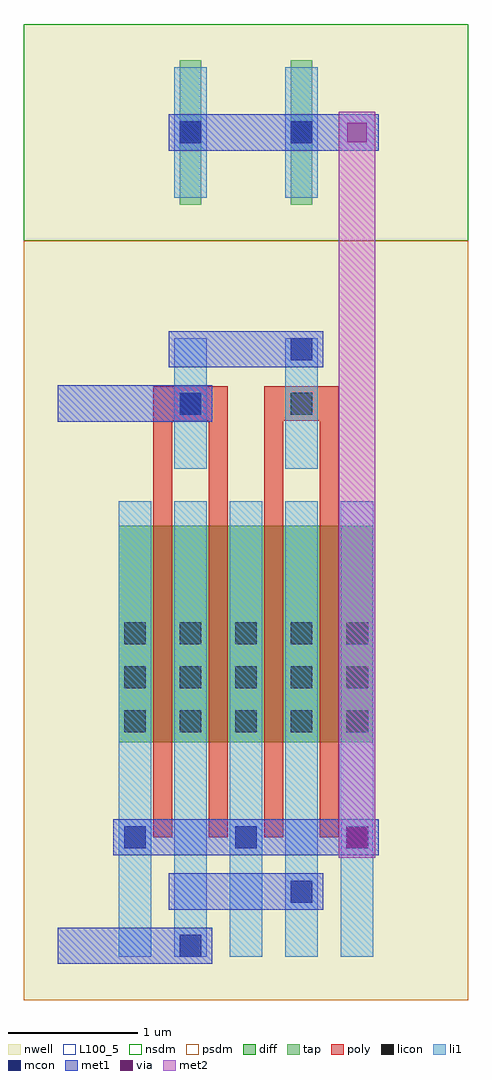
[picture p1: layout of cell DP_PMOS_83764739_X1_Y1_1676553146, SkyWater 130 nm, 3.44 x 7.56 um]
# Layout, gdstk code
import gdstk
lib = gdstk.Library(unit=1e-6, precision=1e-09)
def R(c, l, rs):  # rectangles x0, y0, x1, y1
    for r in rs: c.add(gdstk.rectangle(r[:2], r[2:], *l))
def A(c, l, x, y, w, h, nx, ny, dx, dy):  # array of equal rectangles
    R(c, l, [(x+i*dx, y+j*dy, x+i*dx+w, y+j*dy+h) for i in range(nx) for j in range(ny)])
nwell = (64, 20)
diff = (65, 20)
tap = (65, 44)
poly = (66, 20)
licon = (66, 44)
li1 = (67, 20)
mcon = (67, 44)
met1 = (68, 20)
via = (68, 44)
met2 = (69, 20)
nsdm = (93, 44)
psdm = (94, 20)
L100_5 = (100, 5)

dp_pmos_83764739_x1_y1_1 = lib.new_cell('DP_PMOS_83764739_X1_Y1_1676553146')
R(dp_pmos_83764739_x1_y1_1, nwell, [(0,0,3.44,7.56)])
R(dp_pmos_83764739_x1_y1_1, diff, [(0.735,1.995,2.705,3.675)])
R(dp_pmos_83764739_x1_y1_1, tap, [(1.205,6.16,1.375,7.28), (2.065,6.16,2.235,7.28)])
A(dp_pmos_83764739_x1_y1_1, poly, 1, 1.26, 0.15, 3.36, 4, 1, 0.43, 0)
R(dp_pmos_83764739_x1_y1_1, poly, [(1,4.485,1.58,4.755), (1.86,4.485,2.44,4.755)])
A(dp_pmos_83764739_x1_y1_1, licon, 0.775, 2.075, 0.17, 0.17, 3, 3, 0.43, 0.34)
A(dp_pmos_83764739_x1_y1_1, licon, 1.635, 2.075, 0.17, 0.17, 3, 3, 0.43, 0.34)
R(dp_pmos_83764739_x1_y1_1, licon, [(1.205,4.535,1.375,4.705), (2.065,4.535,2.235,4.705), (1.205,6.635,1.375,6.805), (2.065,6.635,2.235,6.805)])
A(dp_pmos_83764739_x1_y1_1, li1, 0.735, 0.335, 0.25, 3.53, 5, 1, 0.43, 0)
R(dp_pmos_83764739_x1_y1_1, li1, [(1.165,4.115,1.415,5.125), (2.025,4.115,2.275,5.125), (1.165,6.215,1.415,7.225), (2.025,6.215,2.275,7.225)])
A(dp_pmos_83764739_x1_y1_1, mcon, 0.775, 1.175, 0.17, 0.17, 3, 1, 0.86, 0)
R(dp_pmos_83764739_x1_y1_1, mcon, [(1.205,0.335,1.375,0.505), (2.065,0.755,2.235,0.925), (1.205,4.535,1.375,4.705), (2.065,4.955,2.235,5.125), (1.205,6.635,1.375,6.805), (2.065,6.635,2.235,6.805)])
R(dp_pmos_83764739_x1_y1_1, met1, [(0.26,0.28,1.46,0.56), (1.12,0.7,2.32,0.98), (0.69,1.12,2.75,1.4), (0.26,4.48,1.46,4.76), (1.12,4.9,2.32,5.18), (1.12,6.58,2.75,6.86)])
R(dp_pmos_83764739_x1_y1_1, via, [(2.505,1.185,2.655,1.335), (2.505,6.645,2.655,6.795)])
R(dp_pmos_83764739_x1_y1_1, met2, [(2.44,1.1,2.72,6.88)])
R(dp_pmos_83764739_x1_y1_1, nsdm, [(0,5.88,3.44,7.56)])
R(dp_pmos_83764739_x1_y1_1, psdm, [(0,0,3.44,5.88)])
R(dp_pmos_83764739_x1_y1_1, L100_5, [(0,0,3.44,7.56)])

lib.write_gds('DP_PMOS_83764739_X1_Y1_1676553146.gds')
